VERSION 5.7 ;
  NOWIREEXTENSIONATPIN ON ;
  DIVIDERCHAR "/" ;
  BUSBITCHARS "[]" ;
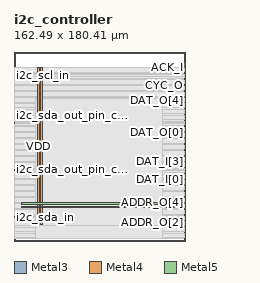
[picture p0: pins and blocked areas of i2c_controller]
MACRO i2c_controller
  CLASS BLOCK ;
  FOREIGN i2c_controller ;
  ORIGIN 0.000 0.000 ;
  SIZE 162.490 BY 180.410 ;
  PIN ACK_I
    DIRECTION INPUT ;
    USE SIGNAL ;
    ANTENNAGATEAREA 0.396000 ;
    PORT
      LAYER Metal3 ;
        RECT 161.930 164.640 162.490 165.200 ;
    END
  END ACK_I
  PIN ADDR_O[0]
    DIRECTION OUTPUT ;
    USE SIGNAL ;
    ANTENNADIFFAREA 0.897600 ;
    PORT
      LAYER Metal3 ;
        RECT 161.930 13.440 162.490 14.000 ;
    END
  END ADDR_O[0]
  PIN ADDR_O[1]
    DIRECTION OUTPUT ;
    USE SIGNAL ;
    ANTENNADIFFAREA 0.897600 ;
    PORT
      LAYER Metal3 ;
        RECT 161.930 19.040 162.490 19.600 ;
    END
  END ADDR_O[1]
  PIN ADDR_O[2]
    DIRECTION OUTPUT ;
    USE SIGNAL ;
    ANTENNADIFFAREA 0.897600 ;
    PORT
      LAYER Metal3 ;
        RECT 161.930 24.640 162.490 25.200 ;
    END
  END ADDR_O[2]
  PIN ADDR_O[3]
    DIRECTION OUTPUT ;
    USE SIGNAL ;
    ANTENNADIFFAREA 0.897600 ;
    PORT
      LAYER Metal3 ;
        RECT 161.930 30.240 162.490 30.800 ;
    END
  END ADDR_O[3]
  PIN ADDR_O[4]
    DIRECTION OUTPUT ;
    USE SIGNAL ;
    ANTENNADIFFAREA 0.897600 ;
    PORT
      LAYER Metal3 ;
        RECT 161.930 35.840 162.490 36.400 ;
    END
  END ADDR_O[4]
  PIN ADDR_O[5]
    DIRECTION OUTPUT ;
    USE SIGNAL ;
    ANTENNADIFFAREA 0.897600 ;
    PORT
      LAYER Metal3 ;
        RECT 161.930 41.440 162.490 42.000 ;
    END
  END ADDR_O[5]
  PIN ADDR_O[6]
    DIRECTION OUTPUT ;
    USE SIGNAL ;
    ANTENNADIFFAREA 0.897600 ;
    PORT
      LAYER Metal3 ;
        RECT 161.930 47.040 162.490 47.600 ;
    END
  END ADDR_O[6]
  PIN ADDR_O[7]
    DIRECTION OUTPUT ;
    USE SIGNAL ;
    ANTENNADIFFAREA 0.897600 ;
    PORT
      LAYER Metal3 ;
        RECT 161.930 52.640 162.490 53.200 ;
    END
  END ADDR_O[7]
  PIN CLK_I
    DIRECTION INPUT ;
    USE SIGNAL ;
    ANTENNAGATEAREA 4.738000 ;
    PORT
      LAYER Metal3 ;
        RECT 161.930 2.240 162.490 2.800 ;
    END
  END CLK_I
  PIN CYC_O
    DIRECTION OUTPUT ;
    USE SIGNAL ;
    ANTENNADIFFAREA 0.897600 ;
    PORT
      LAYER Metal3 ;
        RECT 161.930 147.840 162.490 148.400 ;
    END
  END CYC_O
  PIN DAT_I[0]
    DIRECTION INPUT ;
    USE SIGNAL ;
    ANTENNAGATEAREA 0.396000 ;
    PORT
      LAYER Metal3 ;
        RECT 161.930 58.240 162.490 58.800 ;
    END
  END DAT_I[0]
  PIN DAT_I[1]
    DIRECTION INPUT ;
    USE SIGNAL ;
    ANTENNAGATEAREA 0.396000 ;
    PORT
      LAYER Metal3 ;
        RECT 161.930 63.840 162.490 64.400 ;
    END
  END DAT_I[1]
  PIN DAT_I[2]
    DIRECTION INPUT ;
    USE SIGNAL ;
    ANTENNAGATEAREA 0.396000 ;
    PORT
      LAYER Metal3 ;
        RECT 161.930 69.440 162.490 70.000 ;
    END
  END DAT_I[2]
  PIN DAT_I[3]
    DIRECTION INPUT ;
    USE SIGNAL ;
    ANTENNAGATEAREA 0.396000 ;
    PORT
      LAYER Metal3 ;
        RECT 161.930 75.040 162.490 75.600 ;
    END
  END DAT_I[3]
  PIN DAT_I[4]
    DIRECTION INPUT ;
    USE SIGNAL ;
    ANTENNAGATEAREA 0.396000 ;
    PORT
      LAYER Metal3 ;
        RECT 161.930 80.640 162.490 81.200 ;
    END
  END DAT_I[4]
  PIN DAT_I[5]
    DIRECTION INPUT ;
    USE SIGNAL ;
    ANTENNAGATEAREA 0.396000 ;
    PORT
      LAYER Metal3 ;
        RECT 161.930 86.240 162.490 86.800 ;
    END
  END DAT_I[5]
  PIN DAT_I[6]
    DIRECTION INPUT ;
    USE SIGNAL ;
    ANTENNAGATEAREA 0.396000 ;
    PORT
      LAYER Metal3 ;
        RECT 161.930 91.840 162.490 92.400 ;
    END
  END DAT_I[6]
  PIN DAT_I[7]
    DIRECTION INPUT ;
    USE SIGNAL ;
    ANTENNAGATEAREA 0.396000 ;
    PORT
      LAYER Metal3 ;
        RECT 161.930 97.440 162.490 98.000 ;
    END
  END DAT_I[7]
  PIN DAT_O[0]
    DIRECTION OUTPUT ;
    USE SIGNAL ;
    ANTENNADIFFAREA 0.897600 ;
    PORT
      LAYER Metal3 ;
        RECT 161.930 103.040 162.490 103.600 ;
    END
  END DAT_O[0]
  PIN DAT_O[1]
    DIRECTION OUTPUT ;
    USE SIGNAL ;
    ANTENNADIFFAREA 0.897600 ;
    PORT
      LAYER Metal3 ;
        RECT 161.930 108.640 162.490 109.200 ;
    END
  END DAT_O[1]
  PIN DAT_O[2]
    DIRECTION OUTPUT ;
    USE SIGNAL ;
    ANTENNADIFFAREA 0.897600 ;
    PORT
      LAYER Metal3 ;
        RECT 161.930 114.240 162.490 114.800 ;
    END
  END DAT_O[2]
  PIN DAT_O[3]
    DIRECTION OUTPUT ;
    USE SIGNAL ;
    ANTENNADIFFAREA 0.897600 ;
    PORT
      LAYER Metal3 ;
        RECT 161.930 119.840 162.490 120.400 ;
    END
  END DAT_O[3]
  PIN DAT_O[4]
    DIRECTION OUTPUT ;
    USE SIGNAL ;
    ANTENNADIFFAREA 0.897600 ;
    PORT
      LAYER Metal3 ;
        RECT 161.930 125.440 162.490 126.000 ;
    END
  END DAT_O[4]
  PIN DAT_O[5]
    DIRECTION OUTPUT ;
    USE SIGNAL ;
    ANTENNADIFFAREA 0.897600 ;
    PORT
      LAYER Metal3 ;
        RECT 161.930 131.040 162.490 131.600 ;
    END
  END DAT_O[5]
  PIN DAT_O[6]
    DIRECTION OUTPUT ;
    USE SIGNAL ;
    ANTENNADIFFAREA 0.897600 ;
    PORT
      LAYER Metal3 ;
        RECT 161.930 136.640 162.490 137.200 ;
    END
  END DAT_O[6]
  PIN DAT_O[7]
    DIRECTION OUTPUT ;
    USE SIGNAL ;
    ANTENNADIFFAREA 0.897600 ;
    PORT
      LAYER Metal3 ;
        RECT 161.930 142.240 162.490 142.800 ;
    END
  END DAT_O[7]
  PIN ERR_I
    DIRECTION INPUT ;
    USE SIGNAL ;
    PORT
      LAYER Metal3 ;
        RECT 161.930 170.240 162.490 170.800 ;
    END
  END ERR_I
  PIN RST_I
    DIRECTION INPUT ;
    USE SIGNAL ;
    ANTENNAGATEAREA 0.396000 ;
    PORT
      LAYER Metal3 ;
        RECT 161.930 7.840 162.490 8.400 ;
    END
  END RST_I
  PIN RTY_I
    DIRECTION INPUT ;
    USE SIGNAL ;
    PORT
      LAYER Metal3 ;
        RECT 161.930 175.840 162.490 176.400 ;
    END
  END RTY_I
  PIN STB_O
    DIRECTION OUTPUT ;
    USE SIGNAL ;
    ANTENNADIFFAREA 0.897600 ;
    PORT
      LAYER Metal3 ;
        RECT 161.930 153.440 162.490 154.000 ;
    END
  END STB_O
  PIN VDD
    DIRECTION INOUT ;
    USE POWER ;
    PORT
      LAYER Metal4 ;
        RECT 22.240 15.380 23.840 164.940 ;
    END
    PORT
      LAYER Metal5 ;
        RECT 6.720 31.530 155.680 33.130 ;
    END
  END VDD
  PIN VSS
    DIRECTION INOUT ;
    USE GROUND ;
    PORT
      LAYER Metal4 ;
        RECT 25.540 15.380 27.140 164.940 ;
    END
    PORT
      LAYER Metal5 ;
        RECT 6.720 34.830 155.680 36.430 ;
    END
  END VSS
  PIN WE_O
    DIRECTION OUTPUT ;
    USE SIGNAL ;
    ANTENNADIFFAREA 0.897600 ;
    PORT
      LAYER Metal3 ;
        RECT 161.930 159.040 162.490 159.600 ;
    END
  END WE_O
  PIN i2c_scl_in
    DIRECTION INPUT ;
    USE SIGNAL ;
    ANTENNAGATEAREA 0.396000 ;
    PORT
      LAYER Metal3 ;
        RECT 0.000 156.800 0.560 157.360 ;
    END
  END i2c_scl_in
  PIN i2c_sda_in
    DIRECTION INPUT ;
    USE SIGNAL ;
    ANTENNAGATEAREA 0.396000 ;
    PORT
      LAYER Metal3 ;
        RECT 0.000 22.400 0.560 22.960 ;
    END
  END i2c_sda_in
  PIN i2c_sda_out_pin_ctrl
    DIRECTION OUTPUT ;
    USE SIGNAL ;
    ANTENNADIFFAREA 0.897600 ;
    PORT
      LAYER Metal3 ;
        RECT 0.000 67.200 0.560 67.760 ;
    END
  END i2c_sda_out_pin_ctrl
  PIN i2c_sda_out_pin_ctrl_n
    DIRECTION OUTPUT ;
    USE SIGNAL ;
    ANTENNADIFFAREA 0.897600 ;
    PORT
      LAYER Metal3 ;
        RECT 0.000 112.000 0.560 112.560 ;
    END
  END i2c_sda_out_pin_ctrl_n
  OBS
      LAYER Nwell ;
        RECT 6.290 15.250 156.110 165.070 ;
      LAYER Metal1 ;
        RECT 6.720 15.380 155.680 164.940 ;
      LAYER Metal2 ;
        RECT 7.980 7.930 154.980 165.110 ;
      LAYER Metal3 ;
        RECT 0.560 164.340 161.630 165.060 ;
        RECT 0.560 159.900 161.930 164.340 ;
        RECT 0.560 158.740 161.630 159.900 ;
        RECT 0.560 157.660 161.930 158.740 ;
        RECT 0.860 156.500 161.930 157.660 ;
        RECT 0.560 154.300 161.930 156.500 ;
        RECT 0.560 153.140 161.630 154.300 ;
        RECT 0.560 148.700 161.930 153.140 ;
        RECT 0.560 147.540 161.630 148.700 ;
        RECT 0.560 143.100 161.930 147.540 ;
        RECT 0.560 141.940 161.630 143.100 ;
        RECT 0.560 137.500 161.930 141.940 ;
        RECT 0.560 136.340 161.630 137.500 ;
        RECT 0.560 131.900 161.930 136.340 ;
        RECT 0.560 130.740 161.630 131.900 ;
        RECT 0.560 126.300 161.930 130.740 ;
        RECT 0.560 125.140 161.630 126.300 ;
        RECT 0.560 120.700 161.930 125.140 ;
        RECT 0.560 119.540 161.630 120.700 ;
        RECT 0.560 115.100 161.930 119.540 ;
        RECT 0.560 113.940 161.630 115.100 ;
        RECT 0.560 112.860 161.930 113.940 ;
        RECT 0.860 111.700 161.930 112.860 ;
        RECT 0.560 109.500 161.930 111.700 ;
        RECT 0.560 108.340 161.630 109.500 ;
        RECT 0.560 103.900 161.930 108.340 ;
        RECT 0.560 102.740 161.630 103.900 ;
        RECT 0.560 98.300 161.930 102.740 ;
        RECT 0.560 97.140 161.630 98.300 ;
        RECT 0.560 92.700 161.930 97.140 ;
        RECT 0.560 91.540 161.630 92.700 ;
        RECT 0.560 87.100 161.930 91.540 ;
        RECT 0.560 85.940 161.630 87.100 ;
        RECT 0.560 81.500 161.930 85.940 ;
        RECT 0.560 80.340 161.630 81.500 ;
        RECT 0.560 75.900 161.930 80.340 ;
        RECT 0.560 74.740 161.630 75.900 ;
        RECT 0.560 70.300 161.930 74.740 ;
        RECT 0.560 69.140 161.630 70.300 ;
        RECT 0.560 68.060 161.930 69.140 ;
        RECT 0.860 66.900 161.930 68.060 ;
        RECT 0.560 64.700 161.930 66.900 ;
        RECT 0.560 63.540 161.630 64.700 ;
        RECT 0.560 59.100 161.930 63.540 ;
        RECT 0.560 57.940 161.630 59.100 ;
        RECT 0.560 53.500 161.930 57.940 ;
        RECT 0.560 52.340 161.630 53.500 ;
        RECT 0.560 47.900 161.930 52.340 ;
        RECT 0.560 46.740 161.630 47.900 ;
        RECT 0.560 42.300 161.930 46.740 ;
        RECT 0.560 41.140 161.630 42.300 ;
        RECT 0.560 36.700 161.930 41.140 ;
        RECT 0.560 35.540 161.630 36.700 ;
        RECT 0.560 31.100 161.930 35.540 ;
        RECT 0.560 29.940 161.630 31.100 ;
        RECT 0.560 25.500 161.930 29.940 ;
        RECT 0.560 24.340 161.630 25.500 ;
        RECT 0.560 23.260 161.930 24.340 ;
        RECT 0.860 22.100 161.930 23.260 ;
        RECT 0.560 19.900 161.930 22.100 ;
        RECT 0.560 18.740 161.630 19.900 ;
        RECT 0.560 14.300 161.930 18.740 ;
        RECT 0.560 13.140 161.630 14.300 ;
        RECT 0.560 8.700 161.930 13.140 ;
        RECT 0.560 7.540 161.630 8.700 ;
        RECT 0.560 3.100 161.930 7.540 ;
        RECT 0.560 2.380 161.630 3.100 ;
      LAYER Metal4 ;
        RECT 20.300 15.080 21.940 134.870 ;
        RECT 24.140 15.080 25.240 134.870 ;
        RECT 27.440 15.080 140.980 134.870 ;
        RECT 20.300 2.330 140.980 15.080 ;
  END
END i2c_controller
END LIBRARY

